VERSION 5.7 ;
  NOWIREEXTENSIONATPIN ON ;
  DIVIDERCHAR "/" ;
  BUSBITCHARS "[]" ;
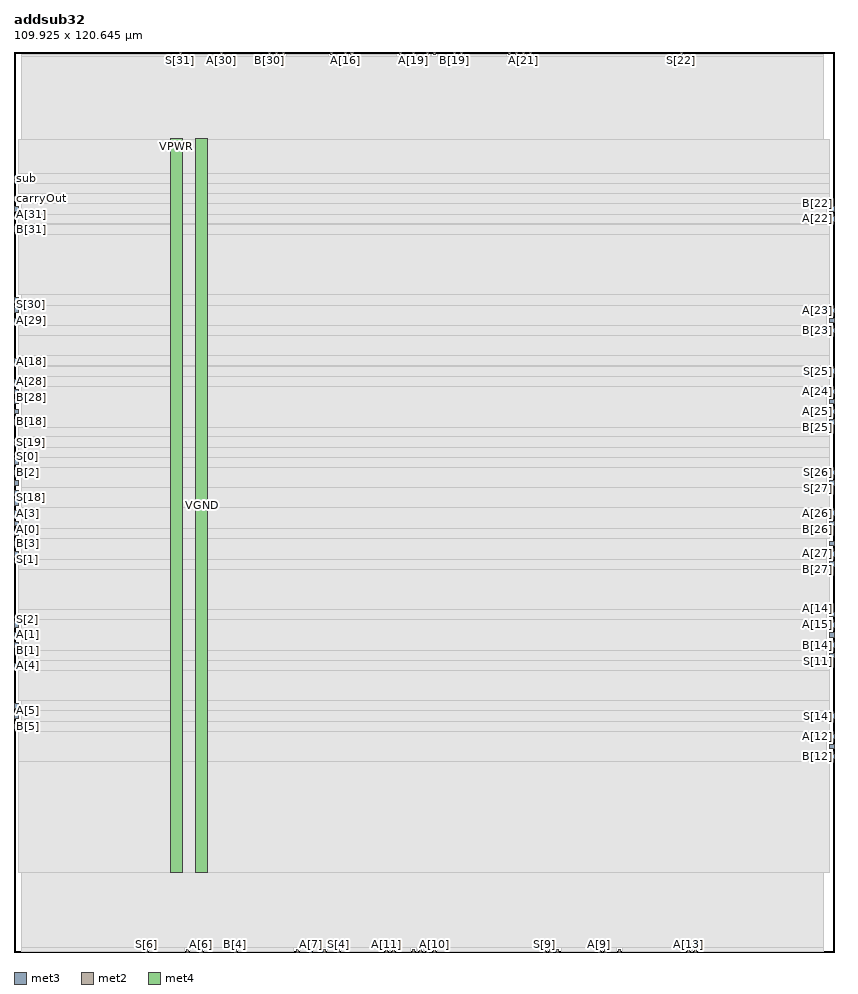
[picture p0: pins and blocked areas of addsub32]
MACRO addsub32
  CLASS BLOCK ;
  FOREIGN addsub32 ;
  ORIGIN 0.000 0.000 ;
  SIZE 109.925 BY 120.645 ;
  PIN A[0]
    DIRECTION INPUT ;
    USE SIGNAL ;
    ANTENNAGATEAREA 0.213000 ;
    PORT
      LAYER met3 ;
        RECT 0.000 57.160 0.600 57.760 ;
    END
  END A[0]
  PIN A[10]
    DIRECTION INPUT ;
    USE SIGNAL ;
    ANTENNAGATEAREA 0.213000 ;
    PORT
      LAYER met2 ;
        RECT 56.210 0.000 56.490 0.280 ;
    END
  END A[10]
  PIN A[11]
    DIRECTION INPUT ;
    USE SIGNAL ;
    ANTENNAGATEAREA 0.213000 ;
    PORT
      LAYER met2 ;
        RECT 49.770 0.000 50.050 0.280 ;
    END
  END A[11]
  PIN A[12]
    DIRECTION INPUT ;
    USE SIGNAL ;
    ANTENNAGATEAREA 0.213000 ;
    PORT
      LAYER met3 ;
        RECT 109.325 28.600 109.925 29.200 ;
    END
  END A[12]
  PIN A[13]
    DIRECTION INPUT ;
    USE SIGNAL ;
    ANTENNAGATEAREA 0.213000 ;
    PORT
      LAYER met2 ;
        RECT 90.250 0.000 90.530 0.280 ;
    END
  END A[13]
  PIN A[14]
    DIRECTION INPUT ;
    USE SIGNAL ;
    ANTENNAGATEAREA 0.213000 ;
    PORT
      LAYER met3 ;
        RECT 109.325 44.920 109.925 45.520 ;
    END
  END A[14]
  PIN A[15]
    DIRECTION INPUT ;
    USE SIGNAL ;
    ANTENNAGATEAREA 0.213000 ;
    PORT
      LAYER met3 ;
        RECT 109.325 43.560 109.925 44.160 ;
    END
  END A[15]
  PIN A[16]
    DIRECTION INPUT ;
    USE SIGNAL ;
    ANTENNAGATEAREA 0.213000 ;
    PORT
      LAYER met2 ;
        RECT 44.250 120.365 44.530 120.645 ;
    END
  END A[16]
  PIN A[17]
    DIRECTION INPUT ;
    USE SIGNAL ;
    ANTENNAGATEAREA 0.213000 ;
    PORT
      LAYER met2 ;
        RECT 35.050 120.365 35.330 120.645 ;
    END
  END A[17]
  PIN A[18]
    DIRECTION INPUT ;
    USE SIGNAL ;
    ANTENNAGATEAREA 0.213000 ;
    PORT
      LAYER met3 ;
        RECT 0.000 78.920 0.600 79.520 ;
    END
  END A[18]
  PIN A[19]
    DIRECTION INPUT ;
    USE SIGNAL ;
    ANTENNAGATEAREA 0.213000 ;
    PORT
      LAYER met2 ;
        RECT 53.450 120.365 53.730 120.645 ;
    END
  END A[19]
  PIN A[1]
    DIRECTION INPUT ;
    USE SIGNAL ;
    ANTENNAGATEAREA 0.213000 ;
    PORT
      LAYER met3 ;
        RECT 0.000 42.200 0.600 42.800 ;
    END
  END A[1]
  PIN A[20]
    DIRECTION INPUT ;
    USE SIGNAL ;
    ANTENNAGATEAREA 0.213000 ;
    PORT
      LAYER met2 ;
        RECT 56.210 120.365 56.490 120.645 ;
    END
  END A[20]
  PIN A[21]
    DIRECTION INPUT ;
    USE SIGNAL ;
    ANTENNAGATEAREA 0.213000 ;
    PORT
      LAYER met2 ;
        RECT 68.170 120.365 68.450 120.645 ;
    END
  END A[21]
  PIN A[22]
    DIRECTION INPUT ;
    USE SIGNAL ;
    ANTENNAGATEAREA 0.213000 ;
    PORT
      LAYER met3 ;
        RECT 109.325 97.960 109.925 98.560 ;
    END
  END A[22]
  PIN A[23]
    DIRECTION INPUT ;
    USE SIGNAL ;
    ANTENNAGATEAREA 0.213000 ;
    PORT
      LAYER met3 ;
        RECT 109.325 85.720 109.925 86.320 ;
    END
  END A[23]
  PIN A[24]
    DIRECTION INPUT ;
    USE SIGNAL ;
    ANTENNAGATEAREA 0.213000 ;
    PORT
      LAYER met3 ;
        RECT 109.325 74.840 109.925 75.440 ;
    END
  END A[24]
  PIN A[25]
    DIRECTION INPUT ;
    USE SIGNAL ;
    ANTENNAGATEAREA 0.213000 ;
    PORT
      LAYER met3 ;
        RECT 109.325 72.120 109.925 72.720 ;
    END
  END A[25]
  PIN A[26]
    DIRECTION INPUT ;
    USE SIGNAL ;
    ANTENNAGATEAREA 0.213000 ;
    PORT
      LAYER met3 ;
        RECT 109.325 58.520 109.925 59.120 ;
    END
  END A[26]
  PIN A[27]
    DIRECTION INPUT ;
    USE SIGNAL ;
    ANTENNAGATEAREA 0.213000 ;
    PORT
      LAYER met3 ;
        RECT 109.325 53.080 109.925 53.680 ;
    END
  END A[27]
  PIN A[28]
    DIRECTION INPUT ;
    USE SIGNAL ;
    ANTENNAGATEAREA 0.213000 ;
    PORT
      LAYER met3 ;
        RECT 0.000 76.200 0.600 76.800 ;
    END
  END A[28]
  PIN A[29]
    DIRECTION INPUT ;
    USE SIGNAL ;
    ANTENNAGATEAREA 0.213000 ;
    PORT
      LAYER met3 ;
        RECT 0.000 84.360 0.600 84.960 ;
    END
  END A[29]
  PIN A[2]
    DIRECTION INPUT ;
    USE SIGNAL ;
    ANTENNAGATEAREA 0.213000 ;
    PORT
      LAYER met3 ;
        RECT 0.000 61.240 0.600 61.840 ;
    END
  END A[2]
  PIN A[30]
    DIRECTION INPUT ;
    USE SIGNAL ;
    ANTENNAGATEAREA 0.213000 ;
    PORT
      LAYER met2 ;
        RECT 27.690 120.365 27.970 120.645 ;
    END
  END A[30]
  PIN A[31]
    DIRECTION INPUT ;
    USE SIGNAL ;
    ANTENNAGATEAREA 0.213000 ;
    PORT
      LAYER met3 ;
        RECT 0.000 99.320 0.600 99.920 ;
    END
  END A[31]
  PIN A[3]
    DIRECTION INPUT ;
    USE SIGNAL ;
    ANTENNAGATEAREA 0.213000 ;
    PORT
      LAYER met3 ;
        RECT 0.000 58.520 0.600 59.120 ;
    END
  END A[3]
  PIN A[4]
    DIRECTION INPUT ;
    USE SIGNAL ;
    ANTENNAGATEAREA 0.213000 ;
    PORT
      LAYER met3 ;
        RECT 0.000 38.120 0.600 38.720 ;
    END
  END A[4]
  PIN A[5]
    DIRECTION INPUT ;
    USE SIGNAL ;
    ANTENNAGATEAREA 0.213000 ;
    PORT
      LAYER met3 ;
        RECT 0.000 31.320 0.600 31.920 ;
    END
  END A[5]
  PIN A[6]
    DIRECTION INPUT ;
    USE SIGNAL ;
    ANTENNAGATEAREA 0.213000 ;
    PORT
      LAYER met2 ;
        RECT 24.930 0.000 25.210 0.280 ;
    END
  END A[6]
  PIN A[7]
    DIRECTION INPUT ;
    USE SIGNAL ;
    ANTENNAGATEAREA 0.213000 ;
    PORT
      LAYER met2 ;
        RECT 39.650 0.000 39.930 0.280 ;
    END
  END A[7]
  PIN A[8]
    DIRECTION INPUT ;
    USE SIGNAL ;
    ANTENNAGATEAREA 0.213000 ;
    PORT
      LAYER met2 ;
        RECT 55.290 0.000 55.570 0.280 ;
    END
  END A[8]
  PIN A[9]
    DIRECTION INPUT ;
    USE SIGNAL ;
    ANTENNAGATEAREA 0.213000 ;
    PORT
      LAYER met2 ;
        RECT 78.290 0.000 78.570 0.280 ;
    END
  END A[9]
  PIN B[0]
    DIRECTION INPUT ;
    USE SIGNAL ;
    ANTENNAGATEAREA 0.126000 ;
    PORT
      LAYER met3 ;
        RECT 0.000 55.800 0.600 56.400 ;
    END
  END B[0]
  PIN B[10]
    DIRECTION INPUT ;
    USE SIGNAL ;
    ANTENNAGATEAREA 0.213000 ;
    PORT
      LAYER met2 ;
        RECT 53.450 0.000 53.730 0.280 ;
    END
  END B[10]
  PIN B[11]
    DIRECTION INPUT ;
    USE SIGNAL ;
    ANTENNAGATEAREA 0.126000 ;
    PORT
      LAYER met2 ;
        RECT 50.690 0.000 50.970 0.280 ;
    END
  END B[11]
  PIN B[12]
    DIRECTION INPUT ;
    USE SIGNAL ;
    ANTENNAGATEAREA 0.213000 ;
    PORT
      LAYER met3 ;
        RECT 109.325 25.880 109.925 26.480 ;
    END
  END B[12]
  PIN B[13]
    DIRECTION INPUT ;
    USE SIGNAL ;
    ANTENNAGATEAREA 0.213000 ;
    PORT
      LAYER met2 ;
        RECT 91.170 0.000 91.450 0.280 ;
    END
  END B[13]
  PIN B[14]
    DIRECTION INPUT ;
    USE SIGNAL ;
    ANTENNAGATEAREA 0.213000 ;
    PORT
      LAYER met3 ;
        RECT 109.325 40.840 109.925 41.440 ;
    END
  END B[14]
  PIN B[15]
    DIRECTION INPUT ;
    USE SIGNAL ;
    ANTENNAGATEAREA 0.213000 ;
    PORT
      LAYER met3 ;
        RECT 109.325 42.200 109.925 42.800 ;
    END
  END B[15]
  PIN B[16]
    DIRECTION INPUT ;
    USE SIGNAL ;
    ANTENNAGATEAREA 0.213000 ;
    PORT
      LAYER met2 ;
        RECT 45.170 120.365 45.450 120.645 ;
    END
  END B[16]
  PIN B[17]
    DIRECTION INPUT ;
    USE SIGNAL ;
    ANTENNAGATEAREA 0.213000 ;
    PORT
      LAYER met2 ;
        RECT 35.970 120.365 36.250 120.645 ;
    END
  END B[17]
  PIN B[18]
    DIRECTION INPUT ;
    USE SIGNAL ;
    ANTENNAGATEAREA 0.213000 ;
    PORT
      LAYER met3 ;
        RECT 0.000 70.760 0.600 71.360 ;
    END
  END B[18]
  PIN B[19]
    DIRECTION INPUT ;
    USE SIGNAL ;
    ANTENNAGATEAREA 0.213000 ;
    PORT
      LAYER met2 ;
        RECT 58.970 120.365 59.250 120.645 ;
    END
  END B[19]
  PIN B[1]
    DIRECTION INPUT ;
    USE SIGNAL ;
    ANTENNAGATEAREA 0.213000 ;
    PORT
      LAYER met3 ;
        RECT 0.000 40.840 0.600 41.440 ;
    END
  END B[1]
  PIN B[20]
    DIRECTION INPUT ;
    USE SIGNAL ;
    ANTENNAGATEAREA 0.213000 ;
    PORT
      LAYER met2 ;
        RECT 55.290 120.365 55.570 120.645 ;
    END
  END B[20]
  PIN B[21]
    DIRECTION INPUT ;
    USE SIGNAL ;
    ANTENNAGATEAREA 0.213000 ;
    PORT
      LAYER met2 ;
        RECT 66.330 120.365 66.610 120.645 ;
    END
  END B[21]
  PIN B[22]
    DIRECTION INPUT ;
    USE SIGNAL ;
    ANTENNAGATEAREA 0.213000 ;
    PORT
      LAYER met3 ;
        RECT 109.325 99.320 109.925 99.920 ;
    END
  END B[22]
  PIN B[23]
    DIRECTION INPUT ;
    USE SIGNAL ;
    ANTENNAGATEAREA 0.213000 ;
    PORT
      LAYER met3 ;
        RECT 109.325 83.000 109.925 83.600 ;
    END
  END B[23]
  PIN B[24]
    DIRECTION INPUT ;
    USE SIGNAL ;
    ANTENNAGATEAREA 0.213000 ;
    PORT
      LAYER met3 ;
        RECT 109.325 73.480 109.925 74.080 ;
    END
  END B[24]
  PIN B[25]
    DIRECTION INPUT ;
    USE SIGNAL ;
    ANTENNAGATEAREA 0.213000 ;
    PORT
      LAYER met3 ;
        RECT 109.325 70.760 109.925 71.360 ;
    END
  END B[25]
  PIN B[26]
    DIRECTION INPUT ;
    USE SIGNAL ;
    ANTENNAGATEAREA 0.213000 ;
    PORT
      LAYER met3 ;
        RECT 109.325 57.160 109.925 57.760 ;
    END
  END B[26]
  PIN B[27]
    DIRECTION INPUT ;
    USE SIGNAL ;
    ANTENNAGATEAREA 0.213000 ;
    PORT
      LAYER met3 ;
        RECT 109.325 51.720 109.925 52.320 ;
    END
  END B[27]
  PIN B[28]
    DIRECTION INPUT ;
    USE SIGNAL ;
    ANTENNAGATEAREA 0.213000 ;
    PORT
      LAYER met3 ;
        RECT 0.000 74.840 0.600 75.440 ;
    END
  END B[28]
  PIN B[29]
    DIRECTION INPUT ;
    USE SIGNAL ;
    ANTENNAGATEAREA 0.213000 ;
    PORT
      LAYER met3 ;
        RECT 0.000 87.080 0.600 87.680 ;
    END
  END B[29]
  PIN B[2]
    DIRECTION INPUT ;
    USE SIGNAL ;
    ANTENNAGATEAREA 0.213000 ;
    PORT
      LAYER met3 ;
        RECT 0.000 63.960 0.600 64.560 ;
    END
  END B[2]
  PIN B[30]
    DIRECTION INPUT ;
    USE SIGNAL ;
    ANTENNAGATEAREA 0.213000 ;
    PORT
      LAYER met2 ;
        RECT 34.130 120.365 34.410 120.645 ;
    END
  END B[30]
  PIN B[31]
    DIRECTION INPUT ;
    USE SIGNAL ;
    ANTENNAGATEAREA 0.213000 ;
    PORT
      LAYER met3 ;
        RECT 0.000 96.600 0.600 97.200 ;
    END
  END B[31]
  PIN B[3]
    DIRECTION INPUT ;
    USE SIGNAL ;
    ANTENNAGATEAREA 0.213000 ;
    PORT
      LAYER met3 ;
        RECT 0.000 54.440 0.600 55.040 ;
    END
  END B[3]
  PIN B[4]
    DIRECTION INPUT ;
    USE SIGNAL ;
    ANTENNAGATEAREA 0.213000 ;
    PORT
      LAYER met2 ;
        RECT 29.530 0.000 29.810 0.280 ;
    END
  END B[4]
  PIN B[5]
    DIRECTION INPUT ;
    USE SIGNAL ;
    ANTENNAGATEAREA 0.213000 ;
    PORT
      LAYER met3 ;
        RECT 0.000 29.960 0.600 30.560 ;
    END
  END B[5]
  PIN B[6]
    DIRECTION INPUT ;
    USE SIGNAL ;
    ANTENNAGATEAREA 0.213000 ;
    PORT
      LAYER met2 ;
        RECT 23.090 0.000 23.370 0.280 ;
    END
  END B[6]
  PIN B[7]
    DIRECTION INPUT ;
    USE SIGNAL ;
    ANTENNAGATEAREA 0.213000 ;
    PORT
      LAYER met2 ;
        RECT 41.490 0.000 41.770 0.280 ;
    END
  END B[7]
  PIN B[8]
    DIRECTION INPUT ;
    USE SIGNAL ;
    ANTENNAGATEAREA 0.213000 ;
    PORT
      LAYER met2 ;
        RECT 54.370 0.000 54.650 0.280 ;
    END
  END B[8]
  PIN B[9]
    DIRECTION INPUT ;
    USE SIGNAL ;
    ANTENNAGATEAREA 0.213000 ;
    PORT
      LAYER met2 ;
        RECT 79.210 0.000 79.490 0.280 ;
    END
  END B[9]
  PIN S[0]
    DIRECTION OUTPUT ;
    USE SIGNAL ;
    ANTENNADIFFAREA 0.702900 ;
    PORT
      LAYER met3 ;
        RECT 0.000 65.320 0.600 65.920 ;
    END
  END S[0]
  PIN S[10]
    DIRECTION OUTPUT ;
    USE SIGNAL ;
    ANTENNAGATEAREA 0.126000 ;
    ANTENNADIFFAREA 0.429000 ;
    PORT
      LAYER met2 ;
        RECT 72.770 0.000 73.050 0.280 ;
    END
  END S[10]
  PIN S[11]
    DIRECTION OUTPUT ;
    USE SIGNAL ;
    ANTENNADIFFAREA 0.383400 ;
    PORT
      LAYER met3 ;
        RECT 109.325 39.480 109.925 40.080 ;
    END
  END S[11]
  PIN S[12]
    DIRECTION OUTPUT ;
    USE SIGNAL ;
    ANTENNADIFFAREA 1.336500 ;
    PORT
      LAYER met2 ;
        RECT 81.050 0.000 81.330 0.280 ;
    END
  END S[12]
  PIN S[13]
    DIRECTION OUTPUT ;
    USE SIGNAL ;
    ANTENNADIFFAREA 1.336500 ;
    PORT
      LAYER met3 ;
        RECT 109.325 27.240 109.925 27.840 ;
    END
  END S[13]
  PIN S[14]
    DIRECTION OUTPUT ;
    USE SIGNAL ;
    ANTENNADIFFAREA 1.336500 ;
    PORT
      LAYER met3 ;
        RECT 109.325 31.320 109.925 31.920 ;
    END
  END S[14]
  PIN S[15]
    DIRECTION OUTPUT ;
    USE SIGNAL ;
    ANTENNADIFFAREA 1.336500 ;
    PORT
      LAYER met3 ;
        RECT 109.325 54.440 109.925 55.040 ;
    END
  END S[15]
  PIN S[16]
    DIRECTION OUTPUT ;
    USE SIGNAL ;
    ANTENNADIFFAREA 0.891000 ;
    PORT
      LAYER met2 ;
        RECT 51.610 120.365 51.890 120.645 ;
    END
  END S[16]
  PIN S[17]
    DIRECTION OUTPUT ;
    USE SIGNAL ;
    ANTENNADIFFAREA 0.891000 ;
    PORT
      LAYER met2 ;
        RECT 42.410 120.365 42.690 120.645 ;
    END
  END S[17]
  PIN S[18]
    DIRECTION OUTPUT ;
    USE SIGNAL ;
    ANTENNADIFFAREA 1.336500 ;
    PORT
      LAYER met3 ;
        RECT 0.000 59.880 0.600 60.480 ;
    END
  END S[18]
  PIN S[19]
    DIRECTION OUTPUT ;
    USE SIGNAL ;
    ANTENNADIFFAREA 0.795200 ;
    PORT
      LAYER met3 ;
        RECT 0.000 68.040 0.600 68.640 ;
    END
  END S[19]
  PIN S[1]
    DIRECTION OUTPUT ;
    USE SIGNAL ;
    ANTENNADIFFAREA 1.336500 ;
    PORT
      LAYER met3 ;
        RECT 0.000 53.080 0.600 53.680 ;
    END
  END S[1]
  PIN S[20]
    DIRECTION OUTPUT ;
    USE SIGNAL ;
    ANTENNADIFFAREA 1.336500 ;
    PORT
      LAYER met2 ;
        RECT 59.890 120.365 60.170 120.645 ;
    END
  END S[20]
  PIN S[21]
    DIRECTION OUTPUT ;
    USE SIGNAL ;
    ANTENNADIFFAREA 1.782000 ;
    PORT
      LAYER met2 ;
        RECT 69.090 120.365 69.370 120.645 ;
    END
  END S[21]
  PIN S[22]
    DIRECTION OUTPUT ;
    USE SIGNAL ;
    ANTENNADIFFAREA 1.782000 ;
    PORT
      LAYER met2 ;
        RECT 89.330 120.365 89.610 120.645 ;
    END
  END S[22]
  PIN S[23]
    DIRECTION OUTPUT ;
    USE SIGNAL ;
    ANTENNADIFFAREA 1.336500 ;
    PORT
      LAYER met3 ;
        RECT 109.325 84.360 109.925 84.960 ;
    END
  END S[23]
  PIN S[24]
    DIRECTION OUTPUT ;
    USE SIGNAL ;
    ANTENNADIFFAREA 1.336500 ;
    PORT
      LAYER met2 ;
        RECT 67.250 120.365 67.530 120.645 ;
    END
  END S[24]
  PIN S[25]
    DIRECTION OUTPUT ;
    USE SIGNAL ;
    ANTENNADIFFAREA 1.336500 ;
    PORT
      LAYER met3 ;
        RECT 109.325 77.560 109.925 78.160 ;
    END
  END S[25]
  PIN S[26]
    DIRECTION OUTPUT ;
    USE SIGNAL ;
    ANTENNADIFFAREA 1.336500 ;
    PORT
      LAYER met3 ;
        RECT 109.325 63.960 109.925 64.560 ;
    END
  END S[26]
  PIN S[27]
    DIRECTION OUTPUT ;
    USE SIGNAL ;
    ANTENNADIFFAREA 1.336500 ;
    PORT
      LAYER met3 ;
        RECT 109.325 62.600 109.925 63.200 ;
    END
  END S[27]
  PIN S[28]
    DIRECTION OUTPUT ;
    USE SIGNAL ;
    ANTENNADIFFAREA 1.336500 ;
    PORT
      LAYER met3 ;
        RECT 0.000 73.480 0.600 74.080 ;
    END
  END S[28]
  PIN S[29]
    DIRECTION OUTPUT ;
    USE SIGNAL ;
    ANTENNADIFFAREA 1.336500 ;
    PORT
      LAYER met3 ;
        RECT 0.000 72.120 0.600 72.720 ;
    END
  END S[29]
  PIN S[2]
    DIRECTION OUTPUT ;
    USE SIGNAL ;
    ANTENNADIFFAREA 0.891000 ;
    PORT
      LAYER met3 ;
        RECT 0.000 43.560 0.600 44.160 ;
    END
  END S[2]
  PIN S[30]
    DIRECTION OUTPUT ;
    USE SIGNAL ;
    ANTENNADIFFAREA 1.336500 ;
    PORT
      LAYER met3 ;
        RECT 0.000 85.720 0.600 86.320 ;
    END
  END S[30]
  PIN S[31]
    DIRECTION OUTPUT ;
    USE SIGNAL ;
    ANTENNADIFFAREA 1.336500 ;
    PORT
      LAYER met2 ;
        RECT 22.170 120.365 22.450 120.645 ;
    END
  END S[31]
  PIN S[3]
    DIRECTION OUTPUT ;
    USE SIGNAL ;
    ANTENNADIFFAREA 1.336500 ;
    PORT
      LAYER met3 ;
        RECT 0.000 62.600 0.600 63.200 ;
    END
  END S[3]
  PIN S[4]
    DIRECTION OUTPUT ;
    USE SIGNAL ;
    ANTENNADIFFAREA 1.336500 ;
    PORT
      LAYER met2 ;
        RECT 43.330 0.000 43.610 0.280 ;
    END
  END S[4]
  PIN S[5]
    DIRECTION OUTPUT ;
    USE SIGNAL ;
    ANTENNADIFFAREA 0.891000 ;
    PORT
      LAYER met3 ;
        RECT 0.000 32.680 0.600 33.280 ;
    END
  END S[5]
  PIN S[6]
    DIRECTION OUTPUT ;
    USE SIGNAL ;
    ANTENNADIFFAREA 1.336500 ;
    PORT
      LAYER met2 ;
        RECT 17.570 0.000 17.850 0.280 ;
    END
  END S[6]
  PIN S[7]
    DIRECTION OUTPUT ;
    USE SIGNAL ;
    ANTENNADIFFAREA 0.891000 ;
    PORT
      LAYER met2 ;
        RECT 37.810 0.000 38.090 0.280 ;
    END
  END S[7]
  PIN S[8]
    DIRECTION OUTPUT ;
    USE SIGNAL ;
    ANTENNADIFFAREA 0.383400 ;
    PORT
      LAYER met2 ;
        RECT 71.850 0.000 72.130 0.280 ;
    END
  END S[8]
  PIN S[9]
    DIRECTION OUTPUT ;
    USE SIGNAL ;
    ANTENNAGATEAREA 0.126000 ;
    ANTENNADIFFAREA 0.429000 ;
    PORT
      LAYER met2 ;
        RECT 70.930 0.000 71.210 0.280 ;
    END
  END S[9]
  PIN VGND
    DIRECTION INOUT ;
    USE GROUND ;
    PORT
      LAYER met4 ;
        RECT 24.340 10.640 25.940 109.040 ;
    END
  END VGND
  PIN VPWR
    DIRECTION INOUT ;
    USE POWER ;
    PORT
      LAYER met4 ;
        RECT 21.040 10.640 22.640 109.040 ;
    END
  END VPWR
  PIN carryOut
    DIRECTION OUTPUT ;
    USE SIGNAL ;
    ANTENNADIFFAREA 0.891000 ;
    PORT
      LAYER met3 ;
        RECT 0.000 100.680 0.600 101.280 ;
    END
  END carryOut
  PIN sub
    DIRECTION INPUT ;
    USE SIGNAL ;
    ANTENNAGATEAREA 0.990000 ;
    PORT
      LAYER met3 ;
        RECT 0.000 103.400 0.600 104.000 ;
    END
  END sub
  OBS
      LAYER nwell ;
        RECT 5.330 10.795 104.150 108.885 ;
      LAYER li1 ;
        RECT 5.520 10.795 103.960 108.885 ;
      LAYER met1 ;
        RECT 0.990 6.160 108.490 115.560 ;
      LAYER met2 ;
        RECT 1.010 120.085 21.890 120.365 ;
        RECT 22.730 120.085 27.410 120.365 ;
        RECT 28.250 120.085 33.850 120.365 ;
        RECT 34.690 120.085 34.770 120.365 ;
        RECT 35.610 120.085 35.690 120.365 ;
        RECT 36.530 120.085 42.130 120.365 ;
        RECT 42.970 120.085 43.970 120.365 ;
        RECT 44.810 120.085 44.890 120.365 ;
        RECT 45.730 120.085 51.330 120.365 ;
        RECT 52.170 120.085 53.170 120.365 ;
        RECT 54.010 120.085 55.010 120.365 ;
        RECT 55.850 120.085 55.930 120.365 ;
        RECT 56.770 120.085 58.690 120.365 ;
        RECT 59.530 120.085 59.610 120.365 ;
        RECT 60.450 120.085 66.050 120.365 ;
        RECT 66.890 120.085 66.970 120.365 ;
        RECT 67.810 120.085 67.890 120.365 ;
        RECT 68.730 120.085 68.810 120.365 ;
        RECT 69.650 120.085 89.050 120.365 ;
        RECT 89.890 120.085 108.470 120.365 ;
        RECT 1.010 0.560 108.470 120.085 ;
        RECT 1.010 0.070 17.290 0.560 ;
        RECT 18.130 0.070 22.810 0.560 ;
        RECT 23.650 0.070 24.650 0.560 ;
        RECT 25.490 0.070 29.250 0.560 ;
        RECT 30.090 0.070 37.530 0.560 ;
        RECT 38.370 0.070 39.370 0.560 ;
        RECT 40.210 0.070 41.210 0.560 ;
        RECT 42.050 0.070 43.050 0.560 ;
        RECT 43.890 0.070 49.490 0.560 ;
        RECT 50.330 0.070 50.410 0.560 ;
        RECT 51.250 0.070 53.170 0.560 ;
        RECT 54.010 0.070 54.090 0.560 ;
        RECT 54.930 0.070 55.010 0.560 ;
        RECT 55.850 0.070 55.930 0.560 ;
        RECT 56.770 0.070 70.650 0.560 ;
        RECT 71.490 0.070 71.570 0.560 ;
        RECT 72.410 0.070 72.490 0.560 ;
        RECT 73.330 0.070 78.010 0.560 ;
        RECT 78.850 0.070 78.930 0.560 ;
        RECT 79.770 0.070 80.770 0.560 ;
        RECT 81.610 0.070 89.970 0.560 ;
        RECT 90.810 0.070 90.890 0.560 ;
        RECT 91.730 0.070 108.470 0.560 ;
      LAYER met3 ;
        RECT 0.600 104.400 109.325 108.965 ;
        RECT 1.000 103.000 109.325 104.400 ;
        RECT 0.600 101.680 109.325 103.000 ;
        RECT 1.000 100.320 109.325 101.680 ;
        RECT 1.000 98.920 108.925 100.320 ;
        RECT 0.600 97.600 108.925 98.920 ;
        RECT 1.000 97.560 108.925 97.600 ;
        RECT 1.000 96.200 109.325 97.560 ;
        RECT 0.600 88.080 109.325 96.200 ;
        RECT 1.000 86.720 109.325 88.080 ;
        RECT 1.000 83.960 108.925 86.720 ;
        RECT 0.600 82.600 108.925 83.960 ;
        RECT 0.600 79.920 109.325 82.600 ;
        RECT 1.000 78.560 109.325 79.920 ;
        RECT 1.000 78.520 108.925 78.560 ;
        RECT 0.600 77.200 108.925 78.520 ;
        RECT 1.000 77.160 108.925 77.200 ;
        RECT 1.000 75.840 109.325 77.160 ;
        RECT 1.000 70.360 108.925 75.840 ;
        RECT 0.600 69.040 109.325 70.360 ;
        RECT 1.000 67.640 109.325 69.040 ;
        RECT 0.600 66.320 109.325 67.640 ;
        RECT 1.000 64.960 109.325 66.320 ;
        RECT 1.000 62.200 108.925 64.960 ;
        RECT 1.000 59.520 109.325 62.200 ;
        RECT 1.000 56.760 108.925 59.520 ;
        RECT 1.000 55.440 109.325 56.760 ;
        RECT 1.000 52.680 108.925 55.440 ;
        RECT 0.600 51.320 108.925 52.680 ;
        RECT 0.600 45.920 109.325 51.320 ;
        RECT 0.600 44.560 108.925 45.920 ;
        RECT 1.000 40.440 108.925 44.560 ;
        RECT 0.600 39.120 108.925 40.440 ;
        RECT 1.000 39.080 108.925 39.120 ;
        RECT 1.000 37.720 109.325 39.080 ;
        RECT 0.600 33.680 109.325 37.720 ;
        RECT 1.000 32.320 109.325 33.680 ;
        RECT 1.000 30.920 108.925 32.320 ;
        RECT 1.000 29.600 109.325 30.920 ;
        RECT 1.000 29.560 108.925 29.600 ;
        RECT 0.600 25.480 108.925 29.560 ;
        RECT 0.600 10.715 109.325 25.480 ;
  END
END addsub32
END LIBRARY

